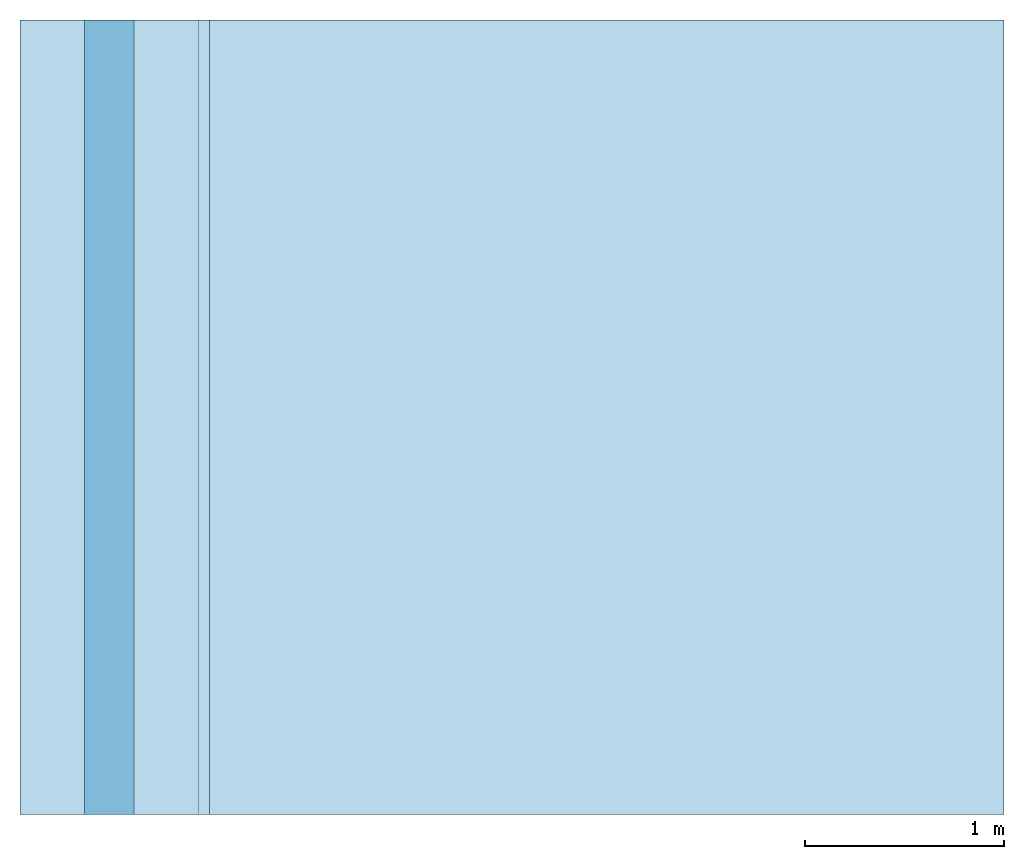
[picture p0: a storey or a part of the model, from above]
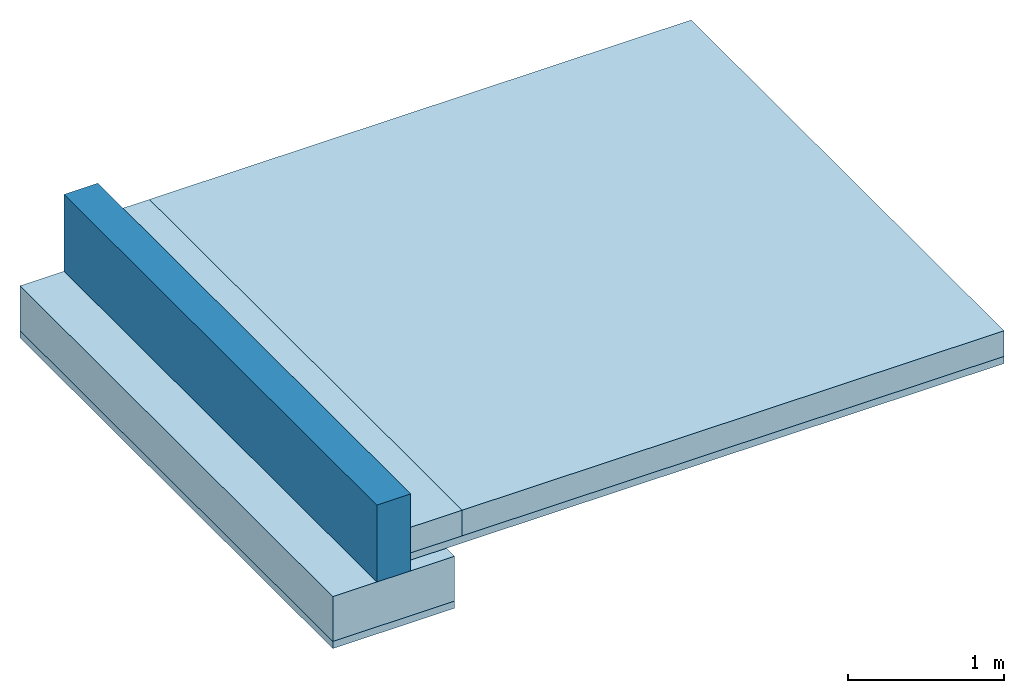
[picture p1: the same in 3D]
Properties of the parts of a building model (IFC2X3)

# File
Description: ViewDefinition [CoordinationView_V2.0]
File name: 0001
Time: 2021-03-09T12:21:08
Written by: The EXPRESS Data Manager Version 5.02.0100.07 : 28 Aug 2013
Made in: 20190108_1515(x64) - Exporter 19.2.1.1 - IU alternativa 19.2.1.1
Comment: STEP Physical File produced by: The EXPRESS Data Manager Version 5.02.0100.07 : 28 Aug 2013 * Module: EDMstepFileFactory/EDMstandAlone * Creation date: Tue Mar 09 12:21:08 2021 * Host: DESKTOP-9PSOHM7 * Database: C:\Users\MODELA~1\AppData\Local\Temp\{58637E73-DB66-45E3-818C-CD966E8BA2E4}\ifc * Database version: 5507 * Database creation date: Tue Mar 09 12:21:08 2021 * Schema: IFC2X3 * Model: DataRepository.ifc * Model creation date: Tue Mar 09 12:21:08 2021 * Header model: DataRepository.ifc_HeaderModel * Header model creation date: Tue Mar 09 12:21:08 2021 * EDMuser: sdai-user * EDMgroup: sdai-group * License ID and type: 5605 : Permanent license. Expiry date: * EDMstepFileFactory options: 020000

# IfcProject, 0001
LongName: Nombre de proyecto; Phase: Estado de proyecto

# IfcSite, Default
RefLatitude: 40, 24, 0, 5493; RefLongitude: -3, -40, -59, -880065; RefElevation: 0 mm

# IfcBuilding
Pset_BuildingCommon - NumberOfStoreys: 1

# IfcBuildingStorey, Nivel 1
LongName: Nivel 1; Elevation: 0 mm

# IfcFooting: Cimentación de muro:ZapataCorrida, Cimentación de muro:ZapataCorrida:140860
In: Nivel 1
PredefinedType: STRIP_FOOTING; Classification: A1010110 Strip Footings (Uniformat); Material: Placa

# IfcSlab: Suelo:Placa (2)
In: Nivel 1
PredefinedType: FLOOR; Material: Placa 200 mm
Pset_SlabCommon - LoadBearing: no; IsExternal: no; PitchAngle: 0 deg; Reference: Placa; ThermalTransmittance: 5.23 kg/K/s3
Name (Suelo:Placa:...)
144760
146260

# IfcSlab: Suelo:ProteccionContraRadon-Radon_Solera_S-RAD-4F (2)
In: Nivel 1
PredefinedType: FLOOR; Material: IM_Polipropileno_Geotextil_GeofimPP12515 2 mm, IM_LaminaAsfaltica_Lamina_PolitaberCombi40 (LBM 40-FP) 2 mm, IM_Polipropileno_Geotextil_GeofimPP12515 2 mm, Hormigón de limpieza 50 mm
Pset_SlabCommon - LoadBearing: no; Reference: ProteccionContraRadon-Radon_Solera_S-RAD-4F; IsExternal: no; ThermalTransmittance: 12.65 kg/K/s3; PitchAngle: 0 deg
Name (Suelo:ProteccionContraRadon-Radon_Solera_S-RAD-4F:...)
143192
146496

# IfcWallStandardCase: Muro básico:Muro, Muro básico:Muro:140814
In: Nivel 1
Type - PredefinedType: STANDARD; Material: Soporte resistente 250 mm
Pset_WallCommon - Reference: Muro; LoadBearing: no; ExtendToStructure: no; IsExternal: yes
